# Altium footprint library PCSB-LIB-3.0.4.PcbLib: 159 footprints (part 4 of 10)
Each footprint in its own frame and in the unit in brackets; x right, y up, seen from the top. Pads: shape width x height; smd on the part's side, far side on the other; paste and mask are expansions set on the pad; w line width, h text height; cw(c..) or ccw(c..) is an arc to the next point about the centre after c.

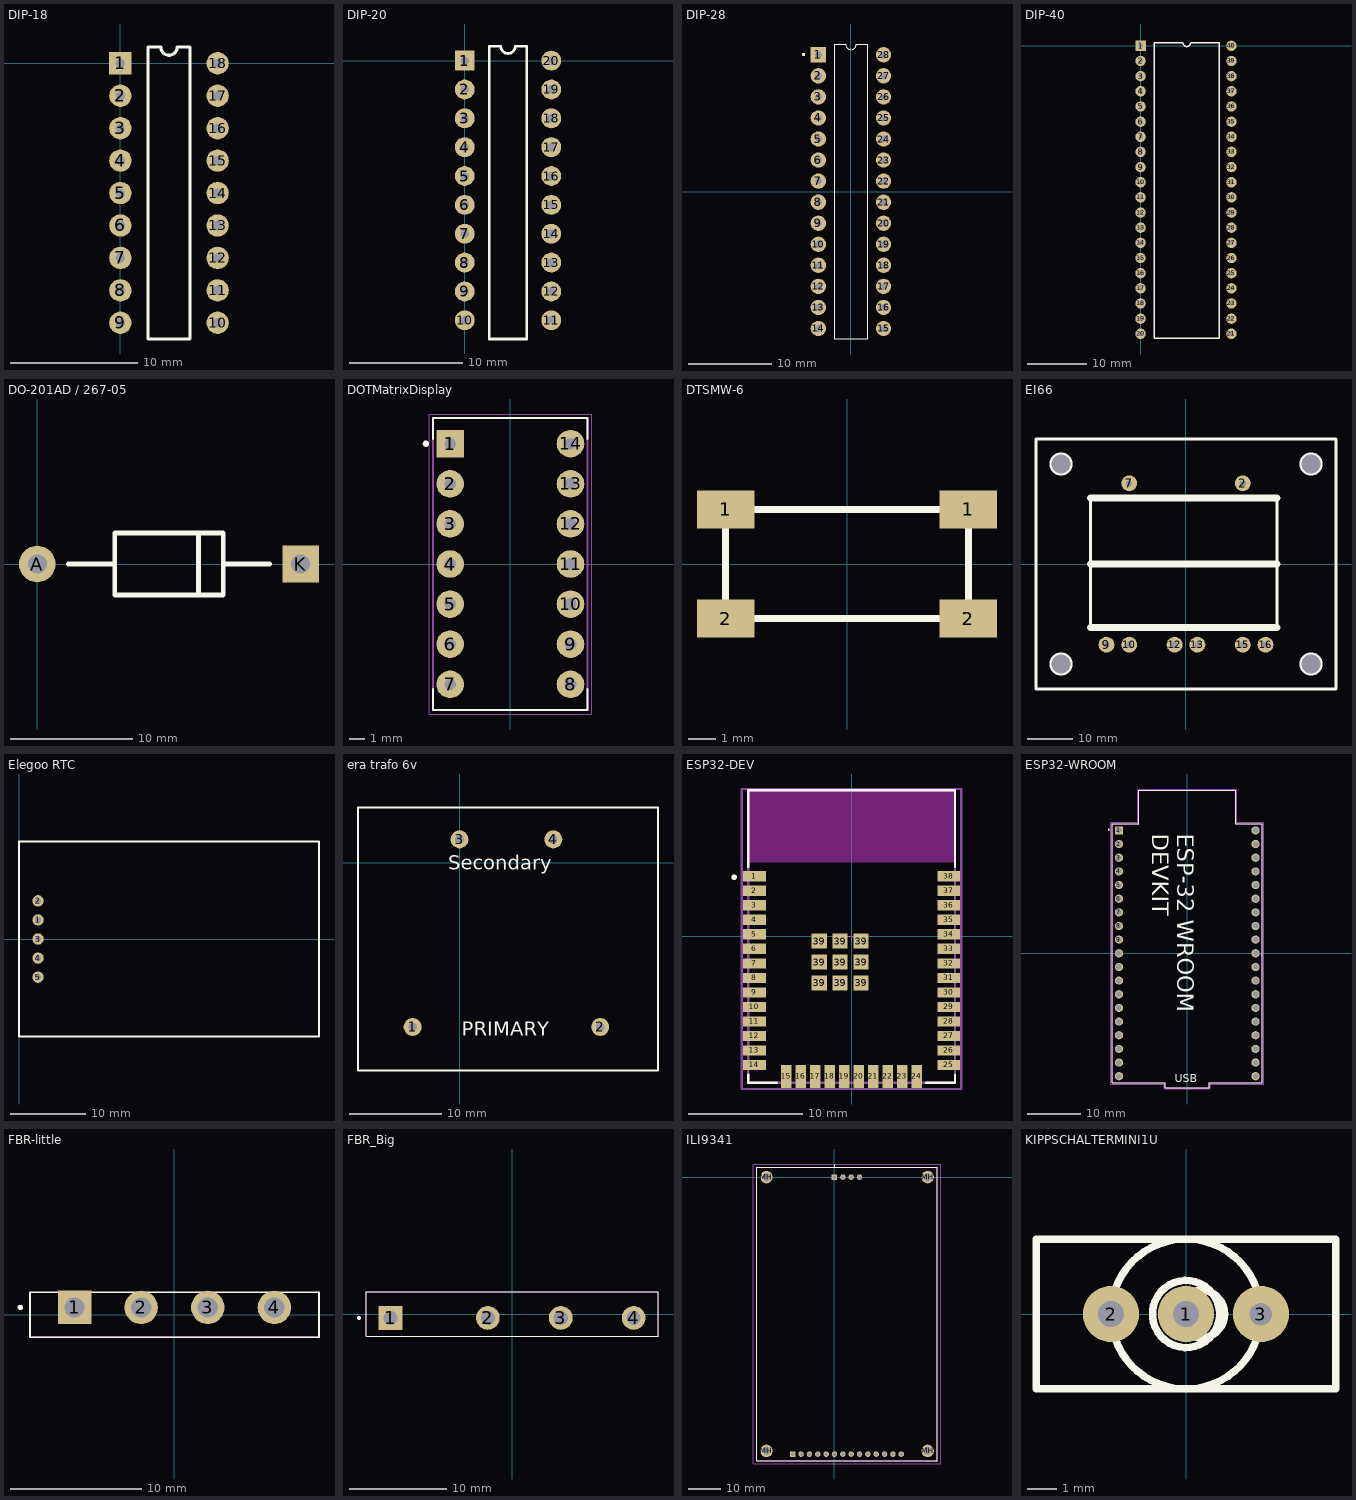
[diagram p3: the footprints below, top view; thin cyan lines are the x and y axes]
## DIP-18 [mm]
pads (18):
  rect 1.75x1.75 hole 0.75: 1(0,0)
  round 1.75 hole 0.75: 2(0,-2.54) 3(0,-5.08) 4(0,-7.62) 5(0,-10.16) 6(0,-12.7) 7(0,-15.24) 8(0,-17.78) 9(0,-20.32) 10(7.62,-20.32) 11(7.62,-17.78) 12(7.62,-15.24) 13(7.62,-12.7) 14(7.62,-10.16) 15(7.62,-7.62) 16(7.62,-5.08) 17(7.62,-2.54) 18(7.62,0)
Top Overlay:
  lines w0.254: 2.159,-21.59 2.159,1.27 3.175,1.27 ccw(c3.81,1.27) 4.445,1.27 5.461,1.27 5.461,-21.59 2.159,-21.59

## DIP-20 [mm]
pads (20):
  rect 1.75x1.75 hole 0.75: 1(0,0)
  round 1.75 hole 0.75: 2(0,-2.54) 3(0,-5.08) 4(0,-7.62) 5(0,-10.16) 6(0,-12.7) 7(0,-15.24) 8(0,-17.78) 9(0,-20.32) 10(0,-22.86) 11(7.62,-22.86) 12(7.62,-20.32) 13(7.62,-17.78) 14(7.62,-15.24) 15(7.62,-12.7) 16(7.62,-10.16) 17(7.62,-7.62) 18(7.62,-5.08) 19(7.62,-2.54) 20(7.62,0)
Top Overlay:
  lines w0.254: 2.159,-24.511 2.159,1.27 3.175,1.27 ccw(c3.81,1.27) 4.445,1.27 5.461,1.27 5.461,-24.511 2.159,-24.511

## DIP-28 [mm]
pads (28):
  rect 1.85x1.85 hole 0.85: 1(-3.935,16.51)
  round 1.85 hole 0.85: 2(-3.935,13.97) 3(-3.935,11.43) 4(-3.935,8.89) 5(-3.935,6.35) 6(-3.935,3.81) 7(-3.935,1.27) 8(-3.935,-1.27) 9(-3.935,-3.81) 10(-3.935,-6.35) 11(-3.935,-8.89) 12(-3.935,-11.43) 13(-3.935,-13.97) 14(-3.935,-16.51) 15(3.935,-16.51) 16(3.935,-13.97) 17(3.935,-11.43) 18(3.935,-8.89) 19(3.935,-6.35) 20(3.935,-3.81) 21(3.935,-1.27) 22(3.935,1.27) 23(3.935,3.81) 24(3.935,6.35) 25(3.935,8.89) 26(3.935,11.43) 27(3.935,13.97) 28(3.935,16.51)
Top Overlay:
  circle w0.2: c-5.714,16.544 r0.1
  lines w0.14: -0.66,17.78 -1,17.78 -2,17.78 -2,-17.78 2,-17.78 2,17.78 ; -0.635,17.78 ccw(c0,17.78) 0.635,17.78 ; 0.642,17.78 1.642,17.78 1.981,17.78
Mechanical 13:
  circle w0.2: c-5.714,16.544 r0.1

## DIP-40 [mm]
pads (40):
  rect 1.75x1.75 hole 0.75: 1(0,0)
  round 1.75 hole 0.75: 2(0,-2.54) 3(0,-5.08) 4(0,-7.62) 5(0,-10.16) 6(0,-12.7) 7(0,-15.24) 8(0,-17.78) 9(0,-20.32) 10(0,-22.86) 11(0,-25.4) 12(0,-27.94) 13(0,-30.48) 14(0,-33.02) 15(0,-35.56) 16(0,-38.1) 17(0,-40.64) 18(0,-43.18) 19(0,-45.72) 20(0,-48.26) 21(15.24,-48.26) 22(15.24,-45.72) 23(15.24,-43.18) 24(15.24,-40.64) 25(15.24,-38.1) 26(15.24,-35.56) 27(15.24,-33.02) 28(15.24,-30.48) 29(15.24,-27.94) 30(15.24,-25.4) 31(15.24,-22.86) 32(15.24,-20.32) 33(15.24,-17.78) 34(15.24,-15.24) 35(15.24,-12.7) 36(15.24,-10.16) 37(15.24,-7.62) 38(15.24,-5.08) 39(15.24,-2.54) 40(15.24,0)
Top Overlay:
  lines w0.254: 2.286,-49.022 2.286,0.508 7.112,0.508 ccw(c7.747,0.508) 8.382,0.508 13.208,0.508 13.208,-49.022 2.286,-49.022

## DO-201AD / 267-05 [mm]
height 5
pads (2):
  round 3 hole 1.55: A(0,0)
  rect 3x3 hole 1.55: K(21.59,0)
Top Overlay:
  lines w0.4: 2.54,0 6.35,0 ; 13.208,-2.54 13.208,2.54 ; 15.24,0 19.05,0 ; 6.35,-2.54 6.35,2.54 15.24,2.54 15.24,-2.54 6.35,-2.54

## DOTMatrixDisplay [mm]
pads (14):
  rect 1.75x1.75 hole 0.75: 1(-3.81,7.62)
  round 1.75 hole 0.75: 2(-3.81,5.08) 3(-3.81,2.54) 4(-3.81,0) 5(-3.81,-2.54) 6(-3.81,-5.08) 7(-3.81,-7.62) 8(3.81,-7.62) 9(3.81,-5.08) 10(3.81,-2.54) 11(3.81,0) 12(3.81,2.54) 13(3.81,5.08) 14(3.81,7.62)
Top Overlay:
  circle w0.2: c-5.35,7.62 r0.1
  lines w0.127: -4.9,-7.92 -4.9,-9.25 4.9,-9.25 4.9,-7.92 ; -4.9,7.92 -4.9,9.25 4.9,9.25 4.9,7.92
Mechanical 13:
  circle w0.2: c-5.35,7.62 r0.1
  lines w0.127: -4.9,-9.25 -4.9,9.25 4.9,9.25 4.9,-9.25 -4.9,-9.25
Mechanical 15:
  lines w0.05: -5.15,-9.5 5.15,-9.5 5.15,9.5 -5.15,9.5 -5.15,-9.5

## DTSMW-6 [mm]
height 17
pads (4):
  rect 2.1x1.4 smd: 1(-4.45,2) 1(4.45,2) 2(-4.45,-2) 2(4.45,-2)
Top Overlay:
  lines w0.254: -4.45,-2 -4.45,2 4.45,2 4.45,-2 -4.45,-2
3D body: height 17, standoff 0, extent -5.602,-2.802 5.602,2.802

## EI66 [mm]
height 52
pads (12):
  round 0 hole 4.2 unplated: 0(-27.5,-22) 0(-27.5,22) 0(27.5,-22) 0(27.5,22)
  round 3.5 hole 1.35 unplated: 2(12.5,17.75) 7(-12.5,17.75) 9(-17.5,-17.75) 10(-12.5,-17.75) 12(-2.5,-17.75) 13(2.5,-17.75) 15(12.5,-17.75) 16(17.5,-17.75)
Top Overlay:
  circle w0.7: c-27.5,22 r2.2
  circle w0.7: c27.5,22 r2.2
  circle w0.7: c-27.5,-22 r2.2
  circle w0.7: c27.5,-22 r2.2
  lines w0.7: -21,-14 -21,14.5 ; 20,-14 20,14.5 ; -33,-27.5 33,-27.5 33,27.5 -33,27.5 -33,-27.5
  lines w1.5: -21,-14 20,-14 ; -21,0 20,0 ; -21,14.5 20,14.5

## Elegoo RTC [mil]
pads (5):
  round 60 hole 30: 1(100,100) 2(100,200) 3(100,0) 4(100,-100) 5(100,-200)
Top Overlay:
  lines w10: 1574.8,0 1574.8,511.81 ; 1574.8,511.81 0,511.81 0,-511.81 1574.8,-511.81 1574.8,511.81

## era trafo 6v [mm]
pads (4):
  round 1.95 hole 0.95: 1(-5.08,-17.78) 2(15.24,-17.78) 3(0,2.54) 4(10.16,2.54)
Top Overlay:
  lines w0.254: -11,-22.5 -11,6 21.5,6 21.5,-22.5 -11,-22.5
  text "Secondary" at -1.246,-0.738 h1.52
  text "PRIMARY" at 0.254,-18.746 h1.52

## ESP32-DEV [mm]
pads (47):
  rect 2x0.9 smd paste+0 mask+0: 1(-8.5,5.26) 2(-8.5,3.99) 3(-8.5,2.72) 4(-8.5,1.45) 5(-8.5,0.18) 6(-8.5,-1.09) 7(-8.5,-2.36) 8(-8.5,-3.63) 9(-8.5,-4.9) 10(-8.5,-6.17) 11(-8.5,-7.44) 12(-8.5,-8.71) 13(-8.5,-9.98) 14(-8.5,-11.25) 25(8.5,-11.25) 26(8.5,-9.98) 27(8.5,-8.71) 28(8.5,-7.44) 29(8.5,-6.17) 30(8.5,-4.9) 31(8.5,-3.63) 32(8.5,-2.36) 33(8.5,-1.09) 34(8.5,0.18) 35(8.5,1.45) 36(8.5,2.72) 37(8.5,3.99) 38(8.5,5.26)
  rect 0.9x2 smd paste+0 mask+0: 15(-5.715,-12.25) 16(-4.445,-12.25) 17(-3.175,-12.25) 18(-1.905,-12.25) 19(-0.635,-12.25) 20(0.635,-12.25) 21(1.905,-12.25) 22(3.175,-12.25) 23(4.445,-12.25) 24(5.715,-12.25)
  rect 1.33x1.33 smd paste+0 mask+0: 39(-2.835,-4.075) 39(-2.835,-2.24) 39(-2.835,-0.405) 39(-1,-4.075) 39(-1,-2.24) 39(-1,-0.405) 39(0.835,-4.075) 39(0.835,-2.24) 39(0.835,-0.405)
Top Overlay:
  circle w0.25: c-10.275,5.185 r0.125
  lines w0.2: -9.05,-12.075 -9.05,-12.8 -6.54,-12.8 ; -9.05,6.085 -9.05,12.8 9.05,12.8 9.05,6.085 ; 6.54,-12.8 9.05,-12.8 9.05,-12.075
Keep-Out Layer:
  rectangle: -9,6.45 9,12.75
  rectangle: -9,6.45 9,12.75
Mechanical 5:
  lines w0.2: -9.6,-13.35 -9.6,12.9 9.6,12.9 9.6,-13.35 -9.6,-13.35
Mechanical 13:
  lines w0.2: -9.05,-12.8 -9.05,12.8 9.05,12.8 9.05,-12.8 -9.05,-12.8
Mechanical 15:
  lines w0.2: -9.6,-13.35 -9.6,12.9 9.6,12.9 9.6,-13.35 -9.6,-13.35
Mechanical 16:
  lines w0.1: -0.5,0 0.5,0 ; 0,-0.5 0,0.5
3D body "UNK_Espressif_Systems_ESP32-WROOM-32D_eec.STEP": height 0.25, standoff 0, extent -9.6,-13.35 9.6,12.9

## ESP32-WROOM [mm]
pads (38):
  rect 1.53x1.53 / inner round 1.53 / far side rect 1.53x1.53 hole 1.02: 1(-12.7,22.85)
  round 1.53 hole 1.02: 2(-12.7,20.31) 3(-12.7,17.77) 4(-12.7,15.23) 5(-12.7,12.69) 6(-12.7,10.15) 7(-12.7,7.61) 8(-12.7,5.07) 9(-12.7,2.53) 10(-12.7,-0.01) 11(-12.7,-2.55) 12(-12.7,-5.09) 13(-12.7,-7.63) 14(-12.7,-10.17) 15(-12.7,-12.71) 16(-12.7,-15.25) 17(-12.7,-17.79) 18(-12.7,-20.33) 19(-12.7,-22.87) 20(12.7,-22.87) 21(12.7,-20.33) 22(12.7,-17.79) 23(12.7,-15.25) 24(12.7,-12.71) 25(12.7,-10.17) 26(12.7,-7.63) 27(12.7,-5.09) 28(12.7,-2.55) 29(12.7,-0.01) 30(12.7,2.53) 31(12.7,5.07) 32(12.7,7.61) 33(12.7,10.15) 34(12.7,12.69) 35(12.7,15.23) 36(12.7,17.77) 37(12.7,20.31) 38(12.7,22.85)
Top Overlay:
  circle w0.2: c-14.57,22.97 r0.1
  lines w0.127: -13.95,-24.1 -13.95,24.1 -9,24.1 -9,30.3 9,30.3 9,24.1 13.95,24.1 13.95,-24.1 4.06,-24.1 4.06,-25 -4.07,-25 -4.07,-24.1 -13.95,-24.1
  text "ESP-32 WROOM / DEVKIT" at -6.477,22.225 h3.05
  text "USB" at -2.286,-24.003 h1.52
Mechanical 13:
  circle w0.2: c-14.57,22.97 r0.1
  lines w0.127: -9,23.876 -9,24.1 -13.95,24.1 -13.95,-24.1 -4.07,-24.1 -4.07,-25 4.06,-25 4.06,-24.1 13.95,-24.1 13.95,24.1 9,24.1 9,23.876
Mechanical 15:
  lines w0.05: -14.2,-24.38 -14.2,24.38 -9.25,24.38 -9.25,30.55 9.25,30.55 9.25,24.38 14.2,24.38 14.2,-24.38 4.31,-24.38 4.31,-25.25 -4.32,-25.25 -4.32,-24.38 -14.2,-24.38

## FBR-little [mm]
pads (4):
  rect 2.55x2.55 hole 1.55: 1(-7.62,0.56)
  round 2.55 hole 1.55: 2(-2.54,0.56) 3(2.54,0.56) 4(7.62,0.56)
Top Overlay:
  circle w0.2: c-11.76,0.56 r0.1
  lines w0.127: -9.095,1.715 -11.025,1.715 ; 9.095,1.715 11.025,1.715 ; -11.025,1.715 11.025,1.715 ; -11.025,1.715 -11.025,-1.715 11.025,-1.715 11.025,1.715
Mechanical 13:
  circle w0.2: c-11.76,0.56 r0.1
  lines w0.127: -11.025,1.715 -11.025,-1.715 11.025,-1.715 11.025,1.715

## FBR_Big [mm]
height 23
pads (4):
  rect 2.45x2.45 hole 1.45: 1(-12.5,-0.4)
  round 2.45 hole 1.45: 2(-2.5,-0.4) 3(5,-0.4) 4(12.5,-0.4)
Top Overlay:
  circle w0.2: c-15.75,-0.4 r0.1
  lines w0.127: -15,-2.3 15,-2.3 15,2.3 -15,2.3 -15,-2.3
Mechanical 13:
  circle w0.2: c-15.75,-0.4 r0.1
  lines w0.127: -15,-2.3 15,-2.3 15,2.3 -15,2.3 -15,-2.3

## ILI9341 [mm]
pads (22):
  rect 1.665x1.665 hole 1.11: A1(0,0) B1(-12.7,-84.3)
  round 1.665 hole 1.11: A2(2.54,0) A3(5.08,0) A4(7.62,0) B2(-10.16,-84.3) B3(-7.62,-84.3) B4(-5.08,-84.3) B5(-2.54,-84.3) B6(0,-84.3) B7(2.54,-84.3) B8(5.08,-84.3) B9(7.62,-84.3) B10(10.16,-84.3) B11(12.7,-84.3) B12(15.24,-84.3) B13(17.78,-84.3) B14(20.32,-84.3)
  round 3.81 hole 2.54: MH(-20.71,-83.3) MH(-20.71,0) MH(28.33,-83.3) MH(28.33,0)
Top Overlay:
  lines w0.1: 0,3.5 ccw(c0,3.55) 0,3.6 ccw(c0,3.55) 0,3.5
  lines w0.2: -23.71,-86.3 31.33,-86.3 31.33,3 -23.71,3 -23.71,-86.3
Mechanical 15:
  lines w0.1: -23.71,-86.3 31.33,-86.3 31.33,3 -23.71,3 -23.71,-86.3
Mechanical 20:
  lines w0.1: -24.71,-87.3 32.33,-87.3 32.33,4 -24.71,4 -24.71,-87.3

## KIPPSCHALTERMINI1U [mil]
pads (3):
  round 75 hole 35: 1(0,0) 2(-100,0)
  round 75 hole 30: 3(100,0)
Top Overlay:
  circle w10: c20,0 r31.62
  circle w10: c0,0 r44.72
  circle w10: c0,0 r100
  lines w10: 0,-30 cw(c0,0) 9.49,28.46 ; -200,-100 -200,100 200,100 200,-100 -200,-100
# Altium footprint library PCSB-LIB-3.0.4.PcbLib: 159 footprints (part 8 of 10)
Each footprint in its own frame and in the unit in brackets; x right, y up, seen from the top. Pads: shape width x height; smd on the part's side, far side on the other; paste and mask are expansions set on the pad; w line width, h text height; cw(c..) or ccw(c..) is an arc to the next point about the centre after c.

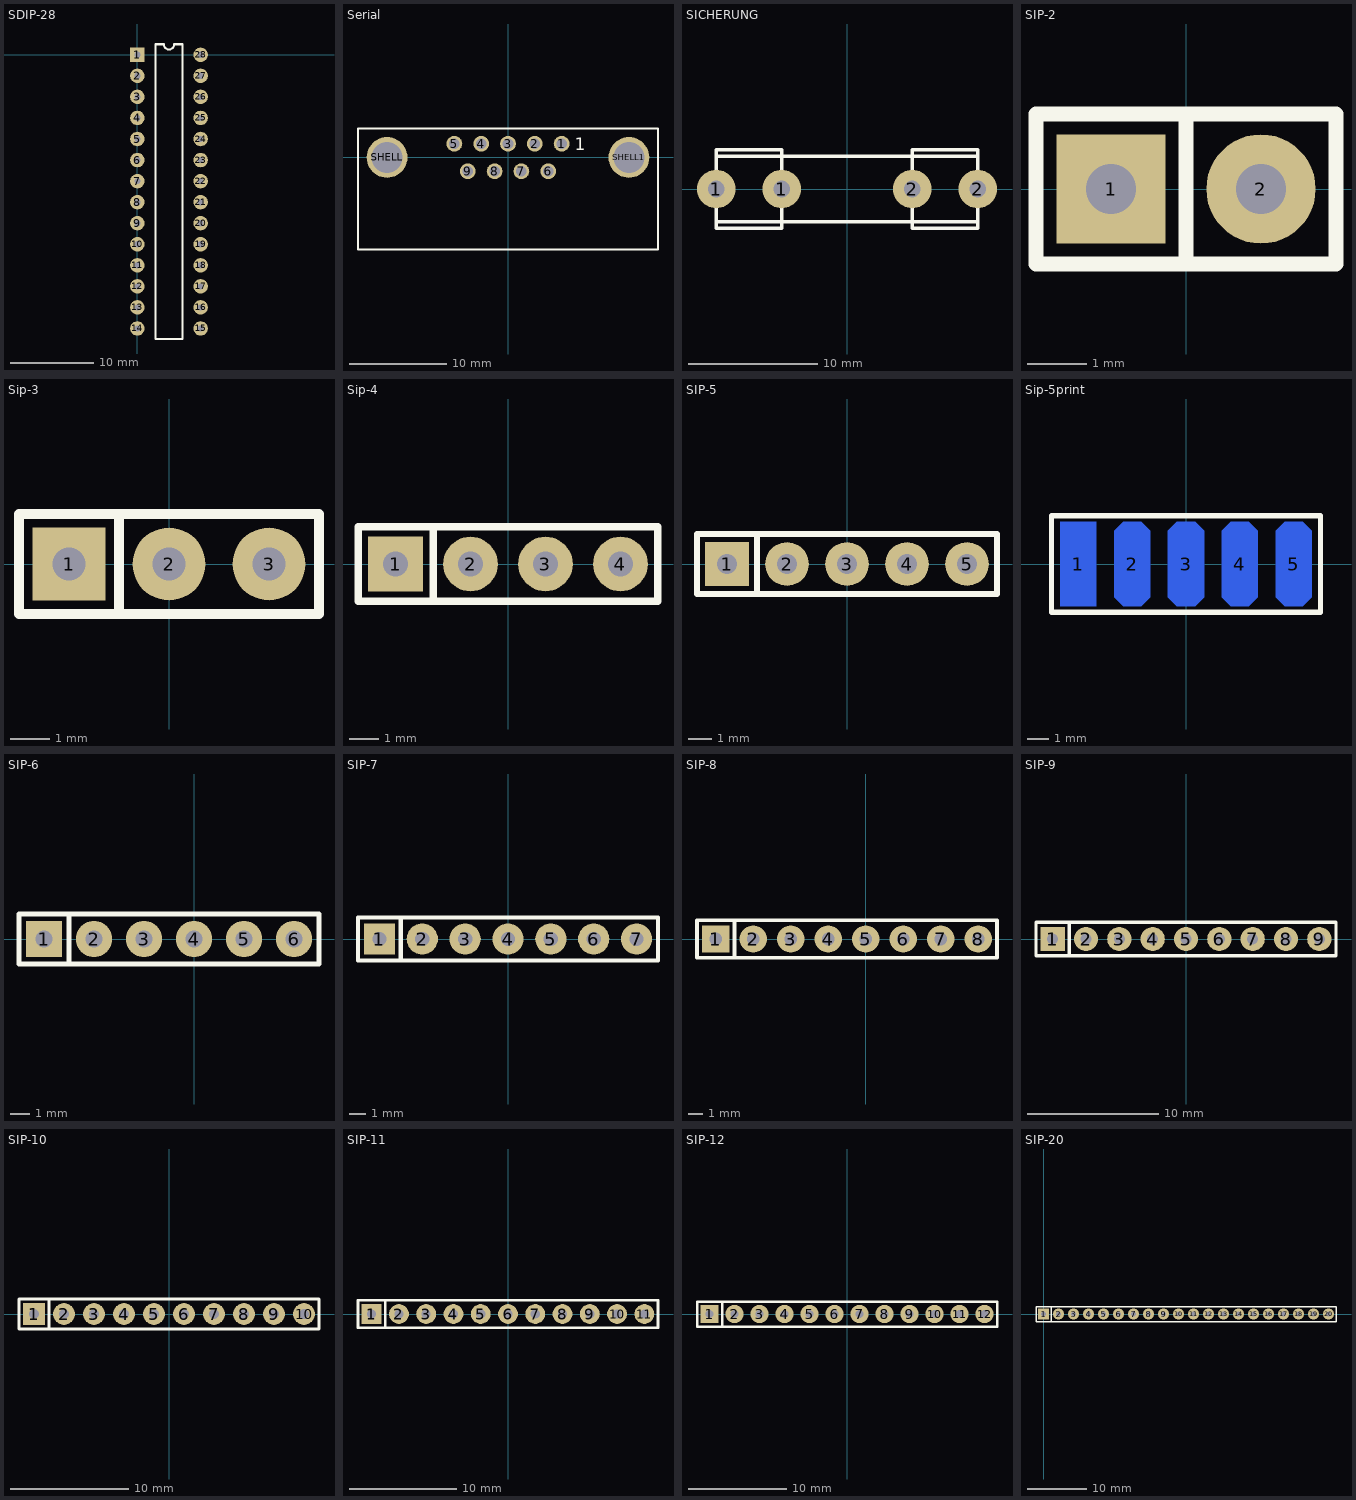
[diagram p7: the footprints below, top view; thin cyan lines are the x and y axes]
## SDIP-28 [mm]
pads (28):
  rect 1.75x1.75 hole 0.75: 1(0,0)
  round 1.75 hole 0.75: 2(0,-2.54) 3(0,-5.08) 4(0,-7.62) 5(0,-10.16) 6(0,-12.7) 7(0,-15.24) 8(0,-17.78) 9(0,-20.32) 10(0,-22.86) 11(0,-25.4) 12(0,-27.94) 13(0,-30.48) 14(0,-33.02) 15(7.62,-33.02) 16(7.62,-30.48) 17(7.62,-27.94) 18(7.62,-25.4) 19(7.62,-22.86) 20(7.62,-20.32) 21(7.62,-17.78) 22(7.62,-15.24) 23(7.62,-12.7) 24(7.62,-10.16) 25(7.62,-7.62) 26(7.62,-5.08) 27(7.62,-2.54) 28(7.62,0)
Top Overlay:
  lines w0.254: 2.159,-34.29 2.159,1.27 3.175,1.27 ccw(c3.81,1.27) 4.445,1.27 5.461,1.27 5.461,-34.29 2.159,-34.29

## Serial [mm]
pads (11):
  round 1.635 hole 1.09: 1(5.54,1.42) 2(2.77,1.42) 3(0,1.42) 4(-2.77,1.42) 5(-5.54,1.42) 6(4.155,-1.42) 7(1.385,-1.42) 8(-1.385,-1.42) 9(-4.155,-1.42)
  round 4.216 hole 3.2: SHELL(-12.5,0) SHELL1(12.5,0)
Top Overlay:
  lines w0.2: -15.5,-9.52 15.5,-9.52 15.5,3 -15.5,3 -15.5,-9.52
  text "1" at 6.915,0.735 h1.27
Mechanical 13:
  text "1" at 6.915,0.735 h1.27

## SICHERUNG [mm]
pads (4):
  round 3 hole 1.3: 1(-10.163,0.008) 1(-5.083,0.008) 2(5.077,0.008) 2(10.157,0.008)
Top Overlay:
  lines w0.254: -10.163,-2.532 -10.163,-3.04 -5.083,-3.04 -5.083,-2.532 -5.083,2.548 -5.083,3.056 -10.163,3.056 -10.163,2.548 ; -10.163,-2.532 10.157,-2.532 ; -10.163,-2.532 -10.163,2.548 ; -10.163,2.548 10.157,2.548 ; 10.157,-2.532 10.157,-3.04 5.077,-3.04 5.077,-2.532 5.077,2.548 5.077,3.056 10.157,3.056 10.157,2.548 ; 10.157,-2.532 10.157,2.548

## SIP-2 [mm]
pads (2):
  rect 1.85x1.85 hole 0.85: 1(-1.27,0)
  round 1.85 hole 0.85: 2(1.27,0)
Top Overlay:
  lines w0.254: 0,-1.27 0,1.27 ; -2.54,-1.27 -2.54,1.27 2.54,1.27 2.54,-1.27 -2.54,-1.27

## Sip-3 [mm]
pads (3):
  rect 1.85x1.85 hole 0.85: 1(-2.54,0)
  round 1.85 hole 0.85: 2(0,0) 3(2.54,0)
Top Overlay:
  lines w0.254: -1.27,-1.27 -1.27,1.27 ; -3.81,-1.27 -3.81,1.27 3.81,1.27 3.81,-1.27 -3.81,-1.27

## Sip-4 [mm]
pads (4):
  rect 1.85x1.85 hole 0.85: 1(-3.81,0)
  round 1.85 hole 0.85: 2(-1.27,0) 3(1.27,0) 4(3.81,0)
Top Overlay:
  lines w0.254: -2.54,-1.27 -2.54,1.27 ; -5.08,-1.27 -5.08,1.27 5.08,1.27 5.08,-1.27 -5.08,-1.27

## SIP-5 [mm]
pads (5):
  rect 1.85x1.85 hole 0.85: 1(-5.08,0)
  round 1.85 hole 0.85: 2(-2.54,0) 3(0,0) 4(2.54,0) 5(5.08,0)
Top Overlay:
  lines w0.254: -3.81,-1.27 -3.81,1.27 ; -6.35,-1.27 6.35,-1.27 6.35,1.27 -6.35,1.27 -6.35,-1.27

## Sip-5print [mm]
pads (5):
  rect 1.7x4 smd far side: 1(-5.08,0)
  oct 1.7x4 smd far side: 2(-2.54,0) 3(0,0) 4(2.54,0) 5(5.08,0)
Top Overlay:
  lines w0.254: -6.35,-2.286 -6.35,2.286 6.35,2.286 6.35,-2.286 -6.35,-2.286

## SIP-6 [mm]
pads (6):
  rect 1.85x1.85 hole 0.85: 1(-7.62,0)
  round 1.85 hole 0.85: 2(-5.08,0) 3(-2.54,0) 4(0,0) 5(2.54,0) 6(5.08,0)
Top Overlay:
  lines w0.254: -6.35,-1.27 -6.35,1.27 ; -8.89,-1.27 -8.89,1.27 6.35,1.27 6.35,-1.27 -8.89,-1.27

## SIP-7 [mm]
pads (7):
  rect 1.85x1.85 hole 0.85: 1(-7.62,0)
  round 1.85 hole 0.85: 2(-5.08,0) 3(-2.54,0) 4(0,0) 5(2.54,0) 6(5.08,0) 7(7.62,0)
Top Overlay:
  lines w0.254: -6.35,-1.27 -6.35,1.27 ; -8.89,-1.27 8.89,-1.27 8.89,1.27 -8.89,1.27 -8.89,-1.27

## SIP-8 [mm]
pads (8):
  rect 1.85x1.85 hole 0.85: 1(-10.16,0)
  round 1.85 hole 0.85: 2(-7.62,0) 3(-5.08,0) 4(-2.54,0) 5(0,0) 6(2.54,0) 7(5.08,0) 8(7.62,0)
Top Overlay:
  lines w0.254: -8.89,-1.27 -8.89,1.27 ; -11.43,-1.27 -11.43,1.27 8.89,1.27 8.89,-1.27 -11.43,-1.27

## SIP-9 [mm]
pads (9):
  rect 1.85x1.85 hole 0.85: 1(-10.16,0)
  round 1.85 hole 0.85: 2(-7.62,0) 3(-5.08,0) 4(-2.54,0) 5(0,0) 6(2.54,0) 7(5.08,0) 8(7.62,0) 9(10.16,0)
Top Overlay:
  lines w0.254: -8.89,-1.27 -8.89,1.27 ; -11.43,-1.27 11.43,-1.27 11.43,1.27 -11.43,1.27 -11.43,-1.27

## SIP-10 [mm]
pads (10):
  rect 1.85x1.85 hole 0.85: 1(-11.43,0)
  round 1.85 hole 0.85: 2(-8.89,0) 3(-6.35,0) 4(-3.81,0) 5(-1.27,0) 6(1.27,0) 7(3.81,0) 8(6.35,0) 9(8.89,0) 10(11.43,0)
Top Overlay:
  lines w0.254: -10.16,-1.27 -10.16,1.27 ; -12.7,-1.27 12.7,-1.27 12.7,1.27 -12.7,1.27 -12.7,-1.27

## SIP-11 [mm]
pads (11):
  rect 1.85x1.85 hole 0.85: 1(-12.7,0)
  round 1.85 hole 0.85: 2(-10.16,0) 3(-7.62,0) 4(-5.08,0) 5(-2.54,0) 6(0,0) 7(2.54,0) 8(5.08,0) 9(7.62,0) 10(10.16,0) 11(12.7,0)
Top Overlay:
  lines w0.254: -11.43,-1.27 -11.43,1.27 ; -13.97,-1.27 -13.97,1.27 13.97,1.27 13.97,-1.27 -13.97,-1.27

## SIP-12 [mm]
pads (12):
  rect 1.85x1.85 hole 0.85: 1(-13.97,0)
  round 1.85 hole 0.85: 2(-11.43,0) 3(-8.89,0) 4(-6.35,0) 5(-3.81,0) 6(-1.27,0) 7(1.27,0) 8(3.81,0) 9(6.35,0) 10(8.89,0) 11(11.43,0) 12(13.97,0)
Top Overlay:
  lines w0.254: -12.7,-1.27 -12.7,1.27 ; -15.24,-1.27 -15.24,1.27 15.24,1.27 15.24,-1.27 -15.24,-1.27

## SIP-20 [mm]
pads (20):
  rect 1.85x1.85 hole 0.85: 1(0,0)
  round 1.85 hole 0.85: 2(2.54,0) 3(5.08,0) 4(7.62,0) 5(10.16,0) 6(12.7,0) 7(15.24,0) 8(17.78,0) 9(20.32,0) 10(22.86,0) 11(25.4,0) 12(27.94,0) 13(30.48,0) 14(33.02,0) 15(35.56,0) 16(38.1,0) 17(40.64,0) 18(43.18,0) 19(45.72,0) 20(48.26,0)
Top Overlay:
  lines w0.254: 1.27,-1.27 1.27,1.27 ; -1.27,-1.27 -1.27,1.27 49.53,1.27 49.53,-1.27 -1.27,-1.27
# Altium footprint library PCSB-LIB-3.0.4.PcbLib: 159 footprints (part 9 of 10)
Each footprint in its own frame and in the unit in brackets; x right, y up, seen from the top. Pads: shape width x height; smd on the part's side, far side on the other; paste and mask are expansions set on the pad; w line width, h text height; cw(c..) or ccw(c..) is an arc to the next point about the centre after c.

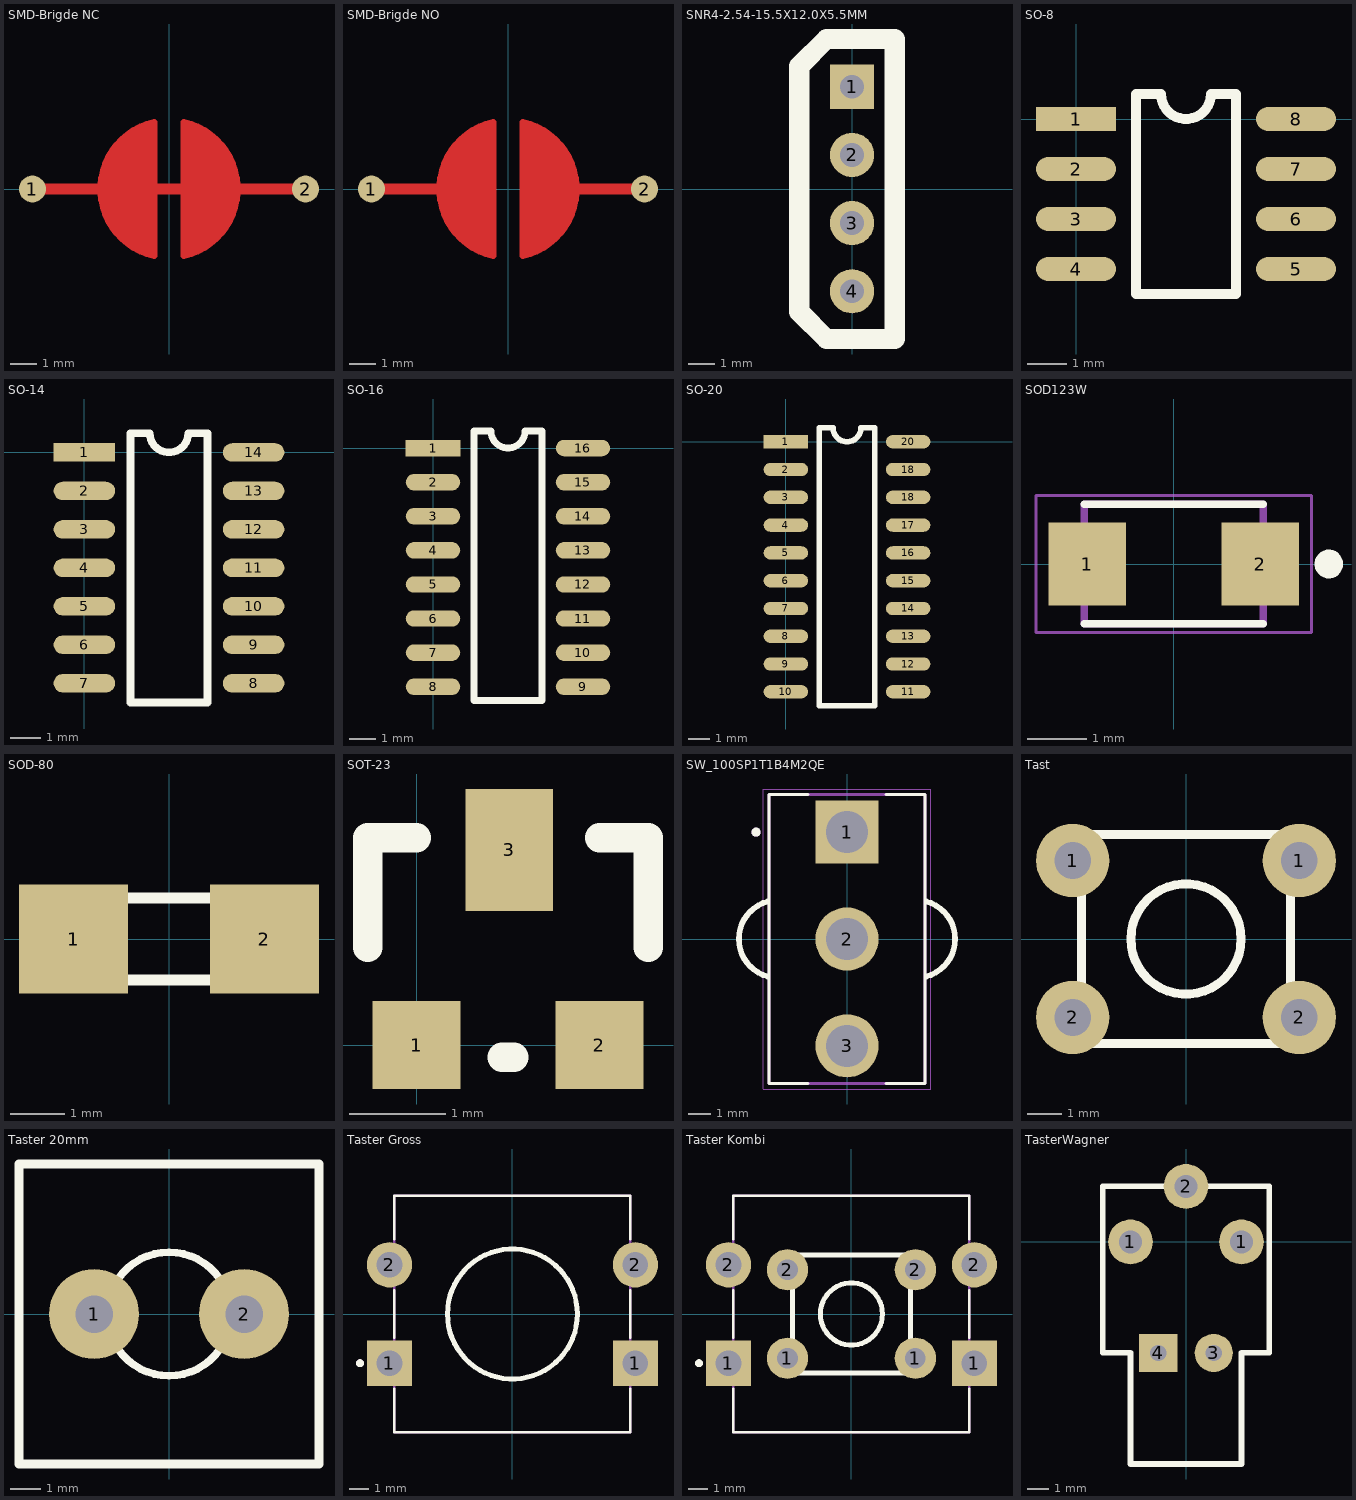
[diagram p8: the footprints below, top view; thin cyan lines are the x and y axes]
## SMD-Brigde NC [mm]
pads (2):
  round 1 smd: 1(-5.08,0) 2(5.08,0)
Top Layer:
  region: 0.551,2.48 0.551,-2.48 0.618,-2.413 1.016,-2.413 1.524,-1.905 1.651,-1.905 2.159,-1.397 2.159,-1.143 2.54,-0.762 2.54,0.762 2.159,1.143 2.159,1.397 1.27,2.286 1.016,2.286 0.762,2.54 0.702,2.48
  region: -0.551,-2.48 -0.551,2.48 -0.618,2.413 -1.016,2.413 -1.524,1.905 -1.651,1.905 -2.159,1.397 -2.159,1.143 -2.54,0.762 -2.54,-0.762 -2.159,-1.143 -2.159,-1.397 -1.27,-2.286 -1.016,-2.286 -0.762,-2.54 -0.702,-2.48
  lines w0.254: -0.551,-2.48 cw(c0,0) -0.551,2.48 -0.551,-2.48 ; 0.551,-2.48 ccw(c0,0) 0.551,2.48 0.551,-2.48
  lines w0.4: -5.08,0 -2.032,0 ; -1.27,0 1.27,0 ; 2.032,0 5.08,0

## SMD-Brigde NO [mm]
pads (2):
  round 1 smd: 1(-5.08,0) 2(5.08,0)
Top Layer:
  region: 0.551,2.48 0.551,-2.48 0.618,-2.413 1.016,-2.413 1.524,-1.905 1.651,-1.905 2.159,-1.397 2.159,-1.143 2.54,-0.762 2.54,0.762 2.159,1.143 2.159,1.397 1.27,2.286 1.016,2.286 0.762,2.54 0.702,2.48
  region: -0.551,-2.48 -0.551,2.48 -0.618,2.413 -1.016,2.413 -1.524,1.905 -1.651,1.905 -2.159,1.397 -2.159,1.143 -2.54,0.762 -2.54,-0.762 -2.159,-1.143 -2.159,-1.397 -1.27,-2.286 -1.016,-2.286 -0.762,-2.54 -0.702,-2.48
  lines w0.254: -0.551,-2.48 cw(c0,0) -0.551,2.48 -0.551,-2.48 ; 0.551,-2.48 ccw(c0,0) 0.551,2.48 0.551,-2.48
  lines w0.4: -5.08,0 -2.032,0 ; 2.032,0 5.08,0

## SNR4-2.54-15.5X12.0X5.5MM [mil]
pads (4):
  rect 65x65 hole 35: 1(0,150)
  round 65 hole 35: 2(0,50) 3(0,-50) 4(0,-150)
Top Overlay:
  lines w29.53: -77.4,-180 -37.4,-220 62.6,-220 62.6,220 -37.4,220 -77.4,180 -77.4,-180

## SO-8 [mil]
pads (8):
  rect 80x24 smd: 1(0,0)
  oval 80x24 smd: 2(0,-50) 3(0,-100) 4(0,-150) 5(220,-150) 6(220,-100) 7(220,-50) 8(220,0)
Top Overlay:
  lines w10: 60,-175 60,25 85,25 ccw(c110,25) 135,25 160,25 160,-175 60,-175

## SO-14 [mil]
pads (14):
  rect 80x24 smd: 1(0,0)
  oval 80x24 smd: 2(0,-50) 3(0,-100) 4(0,-150) 5(0,-200) 6(0,-250) 7(0,-300) 8(220,-300) 9(220,-250) 10(220,-200) 11(220,-150) 12(220,-100) 13(220,-50) 14(220,0)
Top Overlay:
  lines w10: 60,-325 60,25 85,25 ccw(c110,25) 135,25 160,25 160,-325 60,-325

## SO-16 [mil]
pads (16):
  rect 80x24 smd: 1(0,0)
  oval 80x24 smd: 2(0,-50) 3(0,-100) 4(0,-150) 5(0,-200) 6(0,-250) 7(0,-300) 8(0,-350) 9(220,-350) 10(220,-300) 11(220,-250) 12(220,-200) 13(220,-150) 14(220,-100) 15(220,-50) 16(220,0)
Top Overlay:
  lines w10: 60,-370 160,-370 160,25 135,25 cw(c110,25) 85,25 60,25 60,-370

## SO-20 [mil]
pads (20):
  rect 80x24 smd: 1(0,0)
  oval 80x24 smd: 2(0,-50) 3(0,-100) 4(0,-150) 5(0,-200) 6(0,-250) 7(0,-300) 8(0,-350) 9(0,-400) 10(0,-450) 11(220,-450) 12(220,-400) 13(220,-350) 14(220,-300) 15(220,-250) 16(220,-200) 17(220,-150) 18(220,-100) 18(220,-50) 20(220,0)
Top Overlay:
  lines w10: 60,-475 60,25 85,25 ccw(c110,25) 135,25 160,25 160,-475 60,-475

## SOD123W [mm]
pads (2):
  rect 1.3x1.4 smd: 1(-1.45,0) 2(1.45,0)
Top Overlay:
  circle w0.24: c2.6,0 r0.12
  lines w0.127: -1.5,-1 1.5,-1 ; -1.5,1 1.5,1
Mechanical 13:
  lines w0.127: -1.5,-1 -1.5,1 1.5,1 1.5,-1 -1.5,-1
Mechanical 15:
  lines w0.05: -2.31,-1.15 2.31,-1.15 2.31,1.15 -2.31,1.15 -2.31,-1.15

## SOD-80 [mm]
height 1.5
pads (2):
  rect 2x2 smd: 1(-1.75,0) 2(1.75,0)
Top Overlay:
  lines w0.2: 1,-0.75 1,0.75 ; -1.75,-0.75 -1.75,0.75 1.75,0.75 1.75,-0.75 -1.75,-0.75

## SOT-23 [mil]
pads (3):
  rect 36x36 smd: 1(0,0) 2(75,0)
  rect 36x50 smd: 3(38,80)
Top Overlay:
  lines w12: -20,40 -20,85 0,85 ; 35,-5 40,-5 ; 75,85 95,85 95,40

## SW_100SP1T1B4M2QE [mm]
pads (3):
  rect 2.775x2.775 hole 1.85: 1(0,4.7)
  round 2.775 hole 1.85: 2(0,0) 3(0,-4.7)
Top Overlay:
  circle w0.2: c-4,4.7 r0.1
  lines w0.127: -1.71,-6.35 -3.43,-6.35 -3.43,6.35 -1.71,6.35 ; 1.71,-6.35 3.43,-6.35 3.43,6.35 1.71,6.35
  lines w0.254: -3.49,-1.65 cw(c-3.048,0) -3.49,1.65 ; 3.49,-1.65 ccw(c3.048,0) 3.49,1.65
Mechanical 13:
  circle w0.2: c-4,4.7 r0.1
  lines w0.127: -3.43,-6.35 -3.43,6.35 3.43,6.35 3.43,-6.35 -3.43,-6.35
Mechanical 15:
  lines w0.05: -3.68,-6.6 -3.68,6.6 3.68,6.6 3.68,-6.6 -3.68,-6.6

## Tast [mm]
pads (4):
  round 2.1 hole 1.05: 1(-3.25,2.25) 1(3.25,2.25) 2(-3.25,-2.25) 2(3.25,-2.25)
Top Overlay:
  circle w0.254: c0,0 r1.581
  lines w0.254: -3,-3 3,-3 3,3 -3,3 -3,-3

## Taster 20mm [mm]
height 20
pads (2):
  round 3 hole 1.25 unplated: 1(-2.5,0) 2(2.5,0)
Top Overlay:
  circle w0.254: c0,0 r2.062
  lines w0.3: -5,-5 -5,5 5,5 5,-5 -5,-5

## Taster Gross [mm]
height 7.8
pads (4):
  rect 2.3x2.3 hole 1.3: 1(-6.25,-2.5) 1(6.25,-2.5)
  round 2.3 hole 1.3: 2(-6.25,2.5) 2(6.25,2.5)
Top Overlay:
  circle w0.254: c0,0 r3.302
  circle w0.2: c-7.75,-2.5 r0.1
  lines w0.127: -6,-3.788 -6,-6 6,-6 6,-3.788 ; -6,-1.212 -6,1.212 ; -6,3.788 -6,6 6,6 6,3.788 ; 6,-1.212 6,1.212
Mechanical 13:
  circle w0.2: c-7.75,-2.5 r0.1
  lines w0.127: -6,-6 6,-6 6,6 -6,6 -6,-6

## Taster Kombi [mm]
height 7.8
pads (8):
  rect 2.3x2.3 hole 1.3: 1(-6.25,-2.5) 1(6.25,-2.5)
  round 2.1 hole 1.05: 1(-3.25,-2.25) 1(3.25,-2.25) 2(-3.25,2.25) 2(3.25,2.25)
  round 2.3 hole 1.3: 2(-6.25,2.5) 2(6.25,2.5)
Top Overlay:
  circle w0.2: c-7.75,-2.5 r0.1
  circle w0.254: c0,0 r1.581
  lines w0.127: -6,-3.788 -6,-6 6,-6 6,-3.788 ; -6,-1.212 -6,1.212 ; -6,3.788 -6,6 6,6 6,3.788 ; 6,-1.212 6,1.212
  lines w0.254: -3,-3 -3,3 3,3 3,-3 -3,-3
Mechanical 13:
  lines w0.127: -6,-6 -6,6 6,6 6,-6 -6,-6

## TasterWagner [mm]
pads (5):
  round 2.05 hole 1.05: 1(-2.54,0) 1(2.54,0) 2(0,2.54)
  round 1.75 hole 0.75: 3(1.27,-5.08)
  rect 1.75x1.75 hole 0.75: 4(-1.27,-5.08)
Top Overlay:
  lines w0.254: -3.81,-5.08 -2.54,-5.08 -2.54,-10.16 1.905,-10.16 2.54,-10.16 2.54,-5.08 3.81,-5.08 3.81,2.54 -3.81,2.54 -3.81,-5.08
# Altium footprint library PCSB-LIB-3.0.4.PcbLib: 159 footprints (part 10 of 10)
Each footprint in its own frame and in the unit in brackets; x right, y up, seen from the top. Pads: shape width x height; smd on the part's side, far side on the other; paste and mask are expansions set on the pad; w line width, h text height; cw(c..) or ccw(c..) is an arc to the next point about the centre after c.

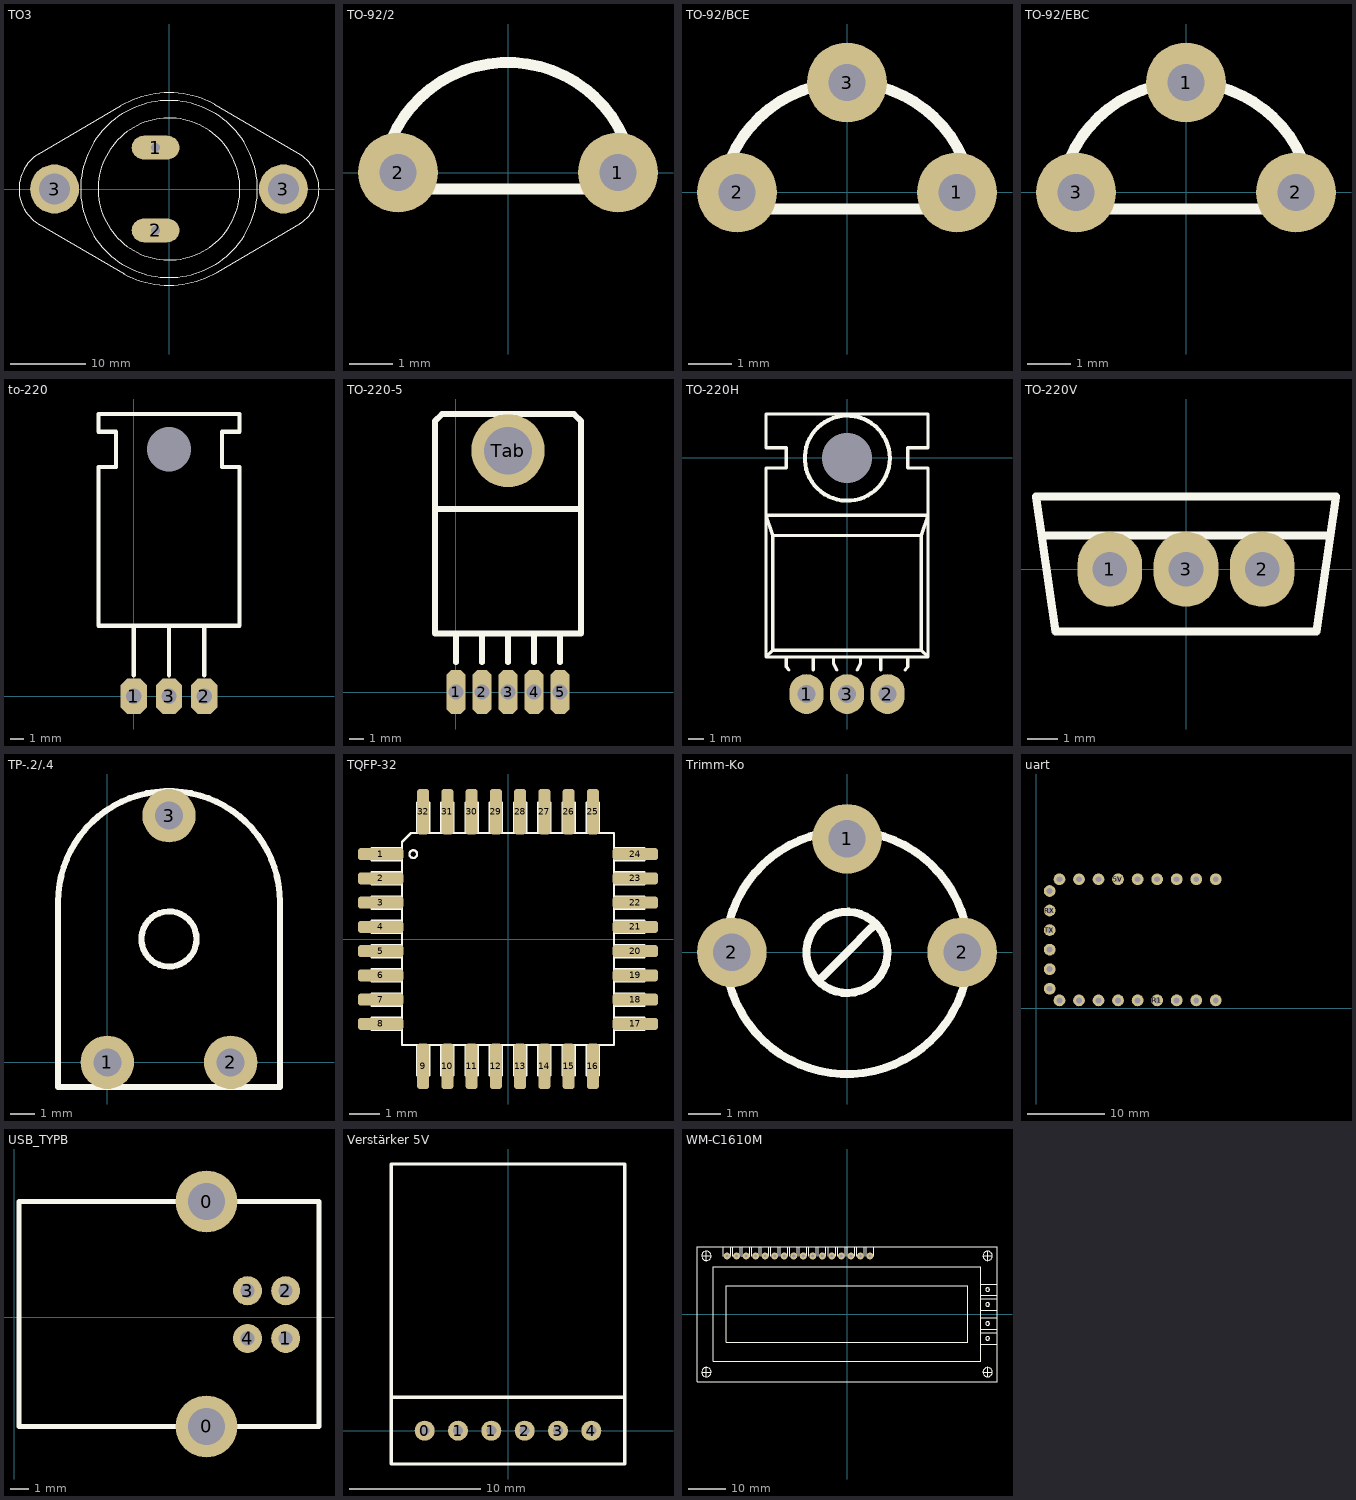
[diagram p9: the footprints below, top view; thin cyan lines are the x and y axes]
## TO3 [mil]
pads (4):
  oval 248x124 hole 47.05: 1(-70,215) 2(-70,-215)
  round 255 hole 162: 3(-595,0) 3(595,0)
Top Overlay:
  circle w6: c0,0 r369
  circle w2: c0,0 r460
  lines w6: -680,180 -250,433 cw(c0,0) 0,500 cw(c0,0) 234.74,441.47 ; -679,-181 -234,-442 ; -676.7,-182.58 cw(c-567,0) -780,0 cw(c-567,0) -673.5,184.46 ; -234.74,-441.47 ccw(c0,0) 0,-500 ccw(c0,0) 250,-433.01 ; 235,441 684,178 ; 251,-433 684,-178 ; 683.01,-178.64 ccw(c567,0) 780,0 ccw(c567,0) 683.01,178.64
Mechanical 13:
  circle w6: c595,0 r85
  circle w6: c-595,0 r85

## TO-92/2 [mm]
pads (2):
  round 1.85 hole 0.85: 1(2.54,0) 2(-2.54,0)
Top Overlay:
  lines w0.254: -2.927,-0.381 cw(c-0.003,-0.381) 2.921,-0.381 -2.927,-0.381

## TO-92/BCE [mm]
pads (3):
  round 1.85 hole 0.85: 1(2.54,0) 2(-2.54,0) 3(0,2.54)
Top Overlay:
  lines w0.254: -2.927,-0.381 cw(c-0.003,-0.381) 2.921,-0.381 -2.927,-0.381

## TO-92/EBC [mm] "Standard-Transistor wie BC546"
pads (3):
  round 1.85 hole 0.85: 1(0,2.54) 2(2.54,0) 3(-2.54,0)
Top Overlay:
  lines w0.254: -2.927,-0.381 cw(c-0.003,-0.381) 2.921,-0.381 -2.927,-0.381

## to-220 [mm]
pads (4):
  round 0 hole 3.2 unplated: 0(2.537,17.788)
  oct 1.905x2.54 hole 1.1: 1(-0.003,0.008) 2(5.077,0.008) 3(2.537,0.008)
Top Overlay:
  lines w0.305: -0.003,1.532 -0.003,5.088 ; 2.537,1.532 2.537,5.088 ; 5.077,1.532 5.077,5.088 ; -2.543,5.088 7.617,5.088 7.617,16.518 6.347,16.518 6.347,19.058 7.617,19.058 7.617,20.328 -2.543,20.328 -2.543,19.058 -1.273,19.058 -1.273,16.518 -2.543,16.518 -2.543,5.088

## TO-220-5 [mm]
height 5
pads (6):
  oct 1.3x3 hole 1.05: 1(0,0) 2(1.778,0) 3(3.556,0) 4(5.334,0) 5(7.112,0)
  round 5 hole 3.25: Tab(3.556,16.5)
Top Overlay:
  lines w0.4: 0,2.032 0,4 ; 1.778,2.032 1.778,4 ; 3.556,2.032 3.556,4 ; 3.556,16.5 3.556,19 ; 5.334,2.032 5.334,4 ; 7.112,2.032 7.112,4 ; -1.444,12.5 -1.444,18.5 -0.944,19 8.056,19 8.556,18.5 ; -1.444,12.5 -1.444,4 8.556,4 8.556,12.5 ; -1.444,12.5 8.556,12.5 ; 8.556,12.5 8.556,18.5 ; 8.556,18.5 8.556,18.5

## TO-220H [mm]
pads (4):
  round 0 hole 3.15: 0(0,0)
  oval 2.15x2.5 hole 1.15: 1(-2.54,-14.817) 2(2.54,-14.817) 3(0,-14.817)
Top Overlay:
  circle w0.254: c0.017,-0.02 r2.667
  lines w0.2: -3.81,-13.123 -3.81,-12.488 ; -3.762,-13.155 -3.647,-13.317 ; -2.117,-13.317 -2.117,-12.488 ; -0.847,-12.488 -0.847,-12.912 -0.635,-13.317 ; 0.635,-13.317 0.847,-12.912 0.847,-12.488 ; 2.117,-13.317 2.117,-12.488 ; 3.655,-13.317 3.818,-13.099 ; 3.81,-13.123 3.81,-12.488 ; -5.08,-12.488 -4.657,-12.065 ; -5.08,-12.488 5.08,-12.488 ; -5.08,-12.488 -5.08,-0.635 -3.81,-0.635 -3.81,0.635 -5.08,0.635 -5.08,2.752 5.08,2.752 5.08,0.635 3.81,0.635 3.81,-0.635 5.08,-0.635 5.08,-12.488 ; -4.657,-12.065 4.657,-12.065 ; -4.657,-12.065 -4.657,-4.868 ; -4.657,-4.868 4.657,-4.868 ; -4.657,-4.868 -5.08,-3.598 5.08,-3.598 4.657,-4.868 ; 4.657,-12.065 5.08,-12.488 ; 4.657,-12.065 4.657,-4.868

## TO-220V [mm]
pads (3):
  oval 2.15x2.5 hole 1.15: 1(-2.54,0) 2(2.54,0) 3(0,0)
Top Overlay:
  lines w0.254: -4.812,1.125 4.808,1.125 ; -5,2.425 -4.35,-2.075 0,-2.075 4.35,-2.075 5,2.425 0,2.425 -5,2.425

## TP-.2/.4 [mm] "Trimpotentiometer liegend klein"
pads (3):
  round 2.2 hole 1.15: 1(0,0) 2(5.08,0) 3(2.54,10.16)
Top Overlay:
  circle w0.254: c2.54,5.08 r1.136
  lines w0.254: -2.032,-1.016 7.112,-1.016 7.112,6.604 ccw(c2.54,6.604) -2.032,6.604 -2.032,-1.016

## TQFP-32 [mm]
height 1.2
pads (32):
  rrect50% 1.5x0.4 smd: 1(-4.2,2.8) 2(-4.2,2) 3(-4.2,1.2) 4(-4.2,0.4) 5(-4.2,-0.4) 6(-4.2,-1.2) 7(-4.2,-2) 8(-4.2,-2.8) 17(4.2,-2.8) 18(4.2,-2) 19(4.2,-1.2) 20(4.2,-0.4) 21(4.2,0.4) 22(4.2,1.2) 23(4.2,2) 24(4.2,2.8)
  rrect50% 0.4x1.5 smd: 9(-2.8,-4.2) 10(-2,-4.2) 11(-1.2,-4.2) 12(-0.4,-4.2) 13(0.4,-4.2) 14(1.2,-4.2) 15(2,-4.2) 16(2.8,-4.2) 25(2.8,4.2) 26(2,4.2) 27(1.2,4.2) 28(0.4,4.2) 29(-0.4,4.2) 30(-1.2,4.2) 31(-2,4.2) 32(-2.8,4.2)
Top Overlay:
  circle w0.076: c-3.127,2.8 r0.127
  lines w0.076: -3.5,-3 -4.5,-3 -4.5,-2.6 -3.5,-2.6 ; -3.5,-2.2 -4.5,-2.2 ; -3.5,-1.8 -4.5,-1.8 ; -3.5,-1.4 -4.5,-1.4 ; -3.5,-1 -4.5,-1 ; -3.5,-0.6 -4.5,-0.6 ; -3.5,-0.2 -4.5,-0.2 ; -3.5,0.2 -4.5,0.2 ; -3.5,0.6 -4.5,0.6 ; -3.5,1 -4.5,1 ; -3.5,1.4 -4.5,1.4 ; -3.5,1.8 -4.5,1.8 ; -3.5,2.2 -4.5,2.2 ; -3.5,2.6 -4.5,2.6 ; -3.5,3 -4.5,3 ; -3,-3.5 -3,-4.5 -2.6,-4.5 -2.6,-3.5 ; -3,3.5 -3,4.5 -2.6,4.5 -2.6,3.5 ; -2.2,-3.5 -2.2,-4.5 ; -2.2,3.5 -2.2,4.5 ; -1.8,-3.5 -1.8,-4.5 ; -1.8,3.5 -1.8,4.5 ; -1.4,-3.5 -1.4,-4.5 ; -1.4,3.5 -1.4,4.5 ; -1,-3.5 -1,-4.5 ; -1,3.5 -1,4.5 ; -0.6,-3.5 -0.6,-4.5 ; -0.6,3.5 -0.6,4.5 ; 0.2,-3.5 0.2,-4.5 ; 0.2,3.5 0.2,4.5 ; 0.6,-3.5 0.6,-4.5 ; 0.6,3.5 0.6,4.5 ; 1,-3.5 1,-4.5 ; 1,3.5 1,4.5 ; 1.4,-3.5 1.4,-4.5 ; 1.4,3.5 1.4,4.5 ; 1.8,-3.5 1.8,-4.5 2.2,-4.5 2.2,-3.5 ; 1.8,3.5 1.8,4.5 ; 2.2,3.5 2.2,4.5 ; 2.6,-3.5 2.6,-4.5 3,-4.5 3,-3.5 ; 2.6,3.5 2.6,4.5 3,4.5 3,3.5 ; 3.5,-3 4.5,-3 ; 3.5,-2.6 4.5,-2.6 ; 3.5,-2.2 4.5,-2.2 ; 3.5,-1.8 4.5,-1.8 ; 3.5,-1.4 4.5,-1.4 ; 3.5,-1 4.5,-1 ; 3.5,-0.6 4.5,-0.6 ; 3.5,-0.2 4.5,-0.2 ; 3.5,0.2 4.5,0.2 ; 3.5,0.6 4.5,0.6 ; 3.5,1 4.5,1 ; 3.5,1.4 4.5,1.4 ; 3.5,1.8 4.5,1.8 ; 3.5,2.2 4.5,2.2 ; 3.5,2.6 4.5,2.6 4.5,3 3.5,3 ; -4.5,-2.2 -4.5,-1.8 ; -4.5,-2.2 -4.5,-1.8 ; -4.5,-1.4 -4.5,-1 ; -4.5,-1.4 -4.5,-1 ; -4.5,-0.6 -4.5,-0.2 ; -4.5,-0.6 -4.5,-0.2 ; -4.5,0.2 -4.5,0.6 ; -4.5,0.2 -4.5,0.6 ; -4.5,1 -4.5,1.4 ; -4.5,1 -4.5,1.4 ; -4.5,1.8 -4.5,2.2 ; -4.5,1.8 -4.5,2.2 ; -4.5,2.6 -4.5,3 ; -4.5,2.6 -4.5,3 ; -3.5,3.2 -3.5,-3.5 3.5,-3.5 3.5,3.5 -3.2,3.5 ; -3.5,3.2 -3.5,3.2 ; -3.5,3.2 -3.2,3.5 ; -3.5,3.2 -3.2,3.5 ; -2.2,-4.5 -1.8,-4.5 ; -2.2,-4.5 -1.8,-4.5 ; -2.2,4.5 -1.8,4.5 ; -2.2,4.5 -1.8,4.5 ; -1.4,-4.5 -1,-4.5 ; -1.4,-4.5 -1,-4.5 ; -1.4,4.5 -1,4.5 ; -1.4,4.5 -1,4.5 ; -0.6,-4.5 -0.2,-4.5 ; -0.6,-4.5 -0.2,-4.5 ; -0.6,4.5 -0.2,4.5 ; -0.6,4.5 -0.2,4.5 ; -0.2,-4.5 -0.2,-3.5 -0.2,-4.5 ; -0.2,4.5 -0.2,3.5 -0.2,4.5 ; 0.2,-4.5 0.6,-4.5 ; 0.2,-4.5 0.6,-4.5 ; 0.2,4.5 0.6,4.5 ; 0.2,4.5 0.6,4.5 ; 1,-4.5 1.4,-4.5 ; 1,-4.5 1.4,-4.5 ; 1,4.5 1.4,4.5 ; 1,4.5 1.4,4.5 ; 1.8,4.5 2.2,4.5 ; 1.8,4.5 2.2,4.5 ; 4.5,-3 4.5,-2.6 ; 4.5,-3 4.5,-2.6 ; 4.5,-2.2 4.5,-1.8 ; 4.5,-2.2 4.5,-1.8 ; 4.5,-1.4 4.5,-1 ; 4.5,-1.4 4.5,-1 ; 4.5,-0.6 4.5,-0.2 ; 4.5,-0.6 4.5,-0.2 ; 4.5,0.2 4.5,0.6 ; 4.5,0.2 4.5,0.6 ; 4.5,1 4.5,1.4 ; 4.5,1 4.5,1.4 ; 4.5,1.8 4.5,2.2 ; 4.5,1.8 4.5,2.2

## Trimm-Ko [mm]
pads (3):
  round 2.15 hole 1.15: 1(0,3.5) 2(-3.55,0) 2(3.55,0)
Top Overlay:
  circle w0.254: c0,0 r1.25
  circle w0.254: c0,0 r3.75
  lines w0.254: -0.762,-0.762 0,0 0.762,0.762

## uart [mil]
pads (24):
  round 60 hole 30: 3V3(520,660) 5V(420,660) CTS(70,200) CTS(620,660) DCD(920,40) DTR(70,600) DTR(220,40) ENTEN(820,660) GND(70,100) GND(120,660) GND(720,40) PWR(920,660) R1(620,40) RSD(820,40) RTS(320,40) RX(70,500) RXC(520,40) RXL(320,660) SLEEP(720,660) TX(70,400) TXD(120,40) TXL(220,660) VCC(70,300) VCC(420,40)
Bottom Overlay:
  lines w10: 0,0 0,708.66 1417.32,708.66 1417.32,0 0,0 ; 1259.84,196.85 1535.43,196.85 1535.43,511.81 1338.58,511.81 1259.84,511.81 1259.84,196.85

## USB_TYPB [mm]
pads (6):
  round 3.3 hole 1.95: 0(10.251,-5.833) 0(10.251,6.167)
  round 1.55 hole 0.75: 1(14.475,-1.134) 2(14.475,1.406) 3(12.443,1.406) 4(12.443,-1.134)
Top Overlay:
  lines w0.254: 16.251,6.107 16.251,-5.833 0.251,-5.833 0.251,6.167 16.251,6.167

## Verstärker 5V [mil]
pads (6):
  round 60 hole 30: 0(-250,0) 1(-150,0) 1(-50,0) 2(50,0) 3(150,0) 4(250,0)
Top Overlay:
  lines w10: -350,100 350,100 ; -350,-100 350,-100 350,800 -350,800 -350,0 -350,-100

## WM-C1610M [mm]
pads (16):
  round 1.85 hole 0.85: 1(-32,15.5) 2(-29.46,15.5) 3(-26.92,15.5) 4(-24.38,15.5) 5(-21.84,15.5) 6(-19.3,15.5) 7(-16.76,15.5) 8(-14.22,15.5) 9(-11.68,15.5) 10(-9.14,15.5) 11(-6.6,15.5) 12(-4.06,15.5) 13(-1.52,15.5) 14(1.02,15.5) 15(3.56,15.5) 16(6.1,15.5)
Top Overlay:
  circle w0.2: c-37.51,15.538 r1.25
  circle w0.2: c-37.51,-15.462 r1.25
  circle w0.2: c37.49,15.538 r1.25
  circle w0.2: c37.49,6.538 r0.5
  circle w0.2: c37.49,2.578 r0.5
  circle w0.2: c37.49,-2.502 r0.5
  circle w0.2: c37.49,-6.462 r0.5
  circle w0.2: c37.49,-15.462 r1.25
  lines w0.1: -38.75,-15.462 -36.26,-15.462 ; -38.75,15.538 -36.26,15.538 ; -37.51,-16.75 -37.51,-14.25 ; -37.51,14.25 -37.51,16.75 ; 36.25,-15.462 38.74,-15.462 ; 36.25,15.538 38.74,15.538 ; 37.49,-16.75 37.49,-14.25 ; 37.49,14.25 37.49,16.75
  lines w0.2: -33.01,15.498 -33.01,18.038 ; -31.01,15.498 -31.01,18.038 ; -30.47,15.498 -30.47,18.038 ; -28.47,15.498 -28.47,18.038 ; -27.93,15.338 -27.93,18.038 ; -25.93,15.338 -25.93,18.038 ; -25.39,15.498 -25.39,18.038 ; -23.39,15.498 -23.39,18.038 ; -22.85,15.498 -22.85,18.038 ; -20.85,15.498 -20.85,18.038 ; -20.31,15.498 -20.31,18.038 ; -18.31,15.498 -18.31,18.038 ; -17.77,15.498 -17.77,18.038 ; -15.77,15.498 -15.77,18.038 ; -15.23,15.498 -15.23,18.038 ; -13.23,15.498 -13.23,18.038 ; -12.69,15.498 -12.69,18.038 ; -10.69,15.498 -10.69,18.038 ; -10.15,15.468 -10.15,18.038 ; -8.15,15.468 -8.15,18.038 ; -7.61,15.468 -7.61,18.038 ; -5.61,15.468 -5.61,18.038 ; -5.07,15.498 -5.07,18.038 ; -3.07,15.498 -3.07,18.038 ; -2.53,15.498 -2.53,18.038 ; -0.53,15.498 -0.53,18.038 ; 0.01,15.498 0.01,18.038 ; 2.01,15.498 2.01,18.038 ; 2.55,15.498 2.55,18.038 ; 4.55,15.498 4.55,18.038 ; 5.09,15.498 5.09,18.038 ; 7.09,15.498 7.09,18.038 ; 35.59,-7.962 39.99,-7.962 ; 35.59,-4.962 39.99,-4.962 ; 35.59,-4.002 39.99,-4.002 ; 35.59,-1.002 39.99,-1.002 ; 35.59,1.078 39.99,1.078 ; 35.59,4.078 39.99,4.078 ; 35.59,5.038 39.99,5.038 ; 35.59,8.038 39.99,8.038 ; -40.01,-17.962 39.99,-17.962 39.99,18.038 -40.01,18.038 -40.01,-17.962 ; -35.61,-12.562 -35.61,12.638 35.59,12.638 35.59,-12.562 -35.61,-12.562 ; -32.24,-7.462 32.22,-7.462 32.22,7.538 -32.24,7.538 -32.24,-7.462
